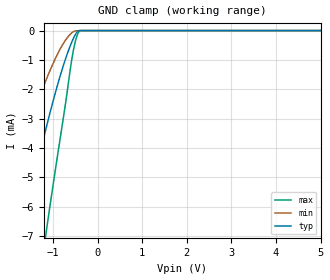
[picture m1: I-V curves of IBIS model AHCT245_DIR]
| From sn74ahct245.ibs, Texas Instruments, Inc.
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[Model]   AHCT245_DIR
Model_type  Input
Vinl = 0.8
Vinh = 2.0
| variable   typ   min   max
C_comp   0.79pF   0.69pF   0.89pF
[Temperature Range]   40   100   -40
| Ambient temperature   25   85   -40
[Voltage range]   5   4.5   5.5
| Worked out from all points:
|   GND clamp passes 1 mA (typ) near -0.73 V on its own axis
[GND Clamp]
| AHCT245_DIR
|   Voltage   I(typ)   I(min)   I(max)
-5V       -33.15mA   -21.35mA   -56.5mA
-2.305V   -11.38mA   -6.9mA     -20.45mA
-2.235V   -10.85mA   -6.552mA   -19.57mA
-1.685V   -6.841mA   -3.92mA    -12.87mA
-1.375V   -4.731mA   -2.562mA   -9.303mA
-1.15V    -3.304mA   -1.668mA   -6.848mA
-815mV    -1.429mA   -565.6uA   -3.447mA
-600mV    -474.1uA   -107.6uA   -1.198mA
-525mV    -214.4uA   -26.87uA   -547.9uA
-450mV    -33.41uA   -5.674uA   -136.4uA
-380mV    -31.37nA   -2.092uA   -158.1nA
5V        33.14pA    81.8pA     25pA
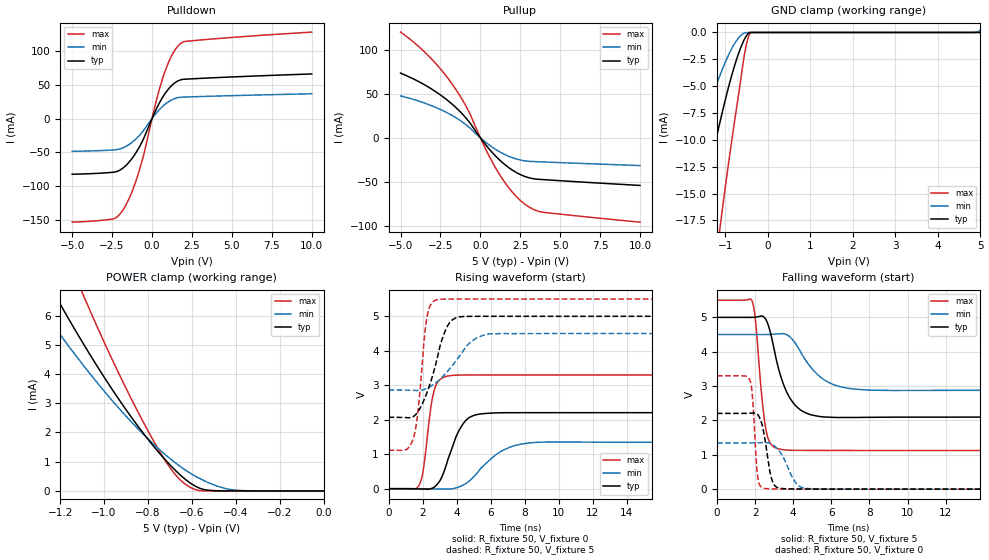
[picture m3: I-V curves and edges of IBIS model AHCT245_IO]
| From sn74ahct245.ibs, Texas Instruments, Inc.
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[Model]   AHCT245_IO
Model_type  I/O
Vinl = 0.8
Vinh = 2.0
Enable   Active-Low
|Vref =   0.0
|Rref =   1000
Cref =   50p
Vmeas =   2.5
| variable   typ   min   max
C_comp   2.72pF   2.51pF   2.83pF
| C_pullup   3.81pF   2.75pF   4.46pF
| C_pulldown   4.07pF   2.72pF   5.53pF
| C_tri-state   2.72pF   2.51pF   2.83pF
[Temperature Range]   40   100   -40
| Ambient temperature   25   85   -40
[Voltage range]   5   4.5   5.5
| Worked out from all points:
|   slope of the pulldown table from 0 to 0.75 V, typ, clamps not added: 21.6 ohm
|   slope of the pullup table from 0 to 0.75 V, typ, clamps not added: 44.5 ohm
|   GND clamp passes 1 mA (typ) near -0.60 V on its own axis
|   POWER clamp passes 1 mA (typ) near -0.71 V on its own axis
|   rising waveform, R_fixture 50, V_fixture 0: 20-80 % time 1.01ns typ, 1.75ns min, 506ps max; typ from 0.001 V to 2.21 V
|   falling waveform, R_fixture 50, V_fixture 5: 20-80 % time 938ps typ, 1.38ns min, 427ps max; typ from 5 V to 2.09 V
|   rising waveform, R_fixture 50, V_fixture 5: 20-80 % time 1.05ns typ, 1.6ns min, 491ps max; typ from 2.07 V to 5 V
|   falling waveform, R_fixture 50, V_fixture 0: 20-80 % time 392ps typ, 726ps min, 214ps max; typ from 2.21 V to 0.001 V
[GND Clamp]
| AHCT245_IO
|   Voltage   I(typ)   I(min)   I(max)
-5V       -97.9mA    -62.15mA   -169.8mA
-2.22V    -30.56mA   -18.04mA   -56.59mA
-1.67V    -18.69mA   -10.41mA   -36.32mA
-1.615V   -17.56mA   -9.697mA   -34.38mA
-1.155V   -8.808mA   -4.261mA   -19.03mA
-1.105V   -7.949mA   -3.748mA   -17.48mA
-810mV    -3.427mA   -1.203mA   -8.944mA
-565mV    -729.5uA   -69.41uA   -2.354mA
-470mV    -126.2uA   -11.19uA   -550.4uA
-380mV    -172.5nA   -4.963uA   -158.1nA
4.8V      97.84pA    1.353uA    90.3pA
5V        113.3pA    205.6uA    97.5pA
[POWER Clamp]
| AHCT245_IO
|   Voltage   I(typ)   I(min)   I(max)
-5V       82.21mA    63.82mA    114.6mA
-1.33V    8.18mA     6.73mA     11.09mA
-1.225V   6.73mA     5.607mA    9.068mA
-1.195V   6.33mA     5.298mA    8.509mA
-1.095V   5.044mA    4.304mA    6.709mA
-940mV    3.214mA    2.893mA    4.131mA
-815mV    1.912mA    1.892mA    2.265mA
-715mV    1.013mA    1.202mA    962.5uA
-640mV    460.2uA    766.3uA    287.9uA
-550mV    55.02uA    371.4uA    480.4nA
-425mV    660.7nA    49.59uA    196.3pA
-84.45fV  113.3pA    284.3pA    124.8pA
[Pulldown]
| AHCT245_IO
|   Voltage   I(typ)   I(min)   I(max)
-5V       -82.26mA   -48.3mA    -153.2mA
-2.43V    -79.28mA   -46.26mA   -148.4mA
-1.745V   -71.72mA   -42.38mA   -132.6mA
-1.255V   -59.05mA   -35.16mA   -108.4mA
-760mV    -40.49mA   -24.14mA   -73.96mA
-460mV    -26.04mA   -15.25mA   -47.89mA
270mV     14.25mA    8.274mA    26.62mA
755mV     34.95mA    20.08mA    65.8mA
1.27V     49.89mA    28.23mA    94.96mA
1.78V     57.41mA    31.75mA    111mA
2.96V     59.59mA    32.74mA    116.4mA
10V       66.25mA    36.88mA    128.2mA
[Pullup]
| AHCT245_IO
|   Voltage   I(typ)   I(min)   I(max)
-5V       73.7mA     47.75mA    120.5mA
-3.3V     58.32mA    38.25mA    94.33mA
-2.53V    49.2mA     32.47mA    79.14mA
-1.83V    39.3mA     26.07mA    62.87mA
-780mV    19.9mA     13.15mA    31.86mA
295mV     -7.066mA   -4.538mA   -11.53mA
1.07V     -22.94mA   -14.49mA   -37.89mA
1.89V     -35.45mA   -21.89mA   -59.47mA
2.705V    -43.49mA   -26.02mA   -74.48mA
3.295V    -46.58mA   -27.03mA   -81.32mA
3.89V     -47.6mA    -27.48mA   -84.82mA
10V       -54.32mA   -31.64mA   -96.19mA
[Ramp]
| AHCT245_IO
| variable   typ   min   max
dV/dt_r   1.33/1.08E-09   0.82/1.90E-09   1.99/5.28E-10
dV/dt_f   1.77/9.62E-10   0.99/1.42E-09   2.64/4.34E-10
R_load = 50
[Rising Waveform]
| AHCT245_IO
R_fixture =   50
C_fixture =   0
L_fixture =   0
V_fixture =   0
V_fixture_min = 0
V_fixture_max = 0
|   Time   V(typ)   V(min)   V(max)
0s        569.1uV    815.2uV    348.3uV
1.805ns   -6.579mV   -13.05uV   110.9mV
2.04ns    -9.438mV   -1.74mV    540.6mV
2.48ns    280.9uV    -4.706mV   2.342V
2.685ns   47.21mV    -6.018mV   2.859V
3.595ns   993.4mV    -6.677mV   3.277V
4.805ns   2.081V     251.3mV    3.299V
6.61ns    2.203V     1.083V     3.298V
8.625ns   2.205V     1.343V     3.298V
50ns      2.205V     1.346V     3.298V
[Falling Waveform]
| AHCT245_IO
R_fixture =   50
C_fixture =   0
L_fixture =   0
V_fixture =   5
V_fixture_min = 4.5
V_fixture_max = 5.5
|   Time   V(typ)   V(min)   V(max)
0s        5V         4.499V     5.5V
1.84ns    4.999V     4.5V       5.481V
2.015ns   5.006V     4.499V     4.937V
2.36ns    5.04V      4.499V     2.656V
2.595ns   4.905V     4.5V       1.663V
3.41ns    3.175V     4.524V     1.153V
4.705ns   2.209V     3.71V      1.128V
5.92ns    2.094V     3.089V     1.127V
7.73ns    2.09V      2.891V     1.126V
50ns      2.094V     2.876V     1.125V
[Rising Waveform]
| AHCT245_IO
R_fixture =   50
C_fixture =   0
L_fixture =   0
V_fixture =   5
V_fixture_min = 4.5
V_fixture_max = 5.5
|   Time   V(typ)   V(min)   V(max)
0s        2.073V     2.865V     1.116V
1.02ns    2.062V     2.86V      1.13V
1.45ns    2.091V     2.853V     1.452V
1.725ns   2.232V     2.85V      2.231V
2.255ns   2.785V     2.911V     4.969V
2.93ns    3.934V     3.136V     5.488V
3.755ns   4.899V     3.579V     5.5V
4.83ns    4.998V     4.253V     5.5V
5.995ns   5.001V     4.491V     5.5V
50ns      5V         4.499V     5.5V
[Falling Waveform]
| AHCT245_IO
R_fixture =   50
C_fixture =   0
L_fixture =   0
V_fixture =   0
V_fixture_min = 0
V_fixture_max = 0
|   Time   V(typ)   V(min)   V(max)
0s        2.205V     1.346V     3.298V
1.75ns    2.211V     1.346V     3.143V
1.865ns   2.216V     1.347V     2.673V
2.14ns    2.169V     1.35V      352.6mV
2.555ns   1.323V     1.353V     18.26mV
2.95ns    179.2mV    1.281V     7.83mV
3.625ns   11.82mV    758.6mV    1.935mV
4.215ns   5.16mV     134.2mV    722.5uV
4.96ns    2.418mV    10.7mV     191uV
50ns      544.9uV    831.4uV    341uV
